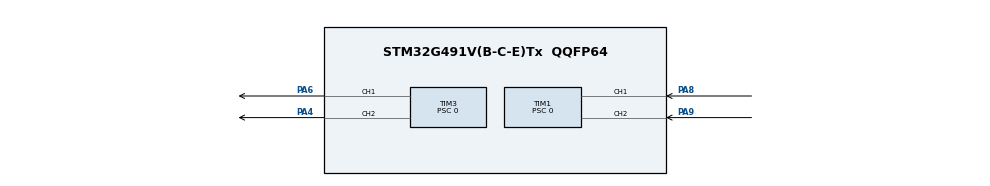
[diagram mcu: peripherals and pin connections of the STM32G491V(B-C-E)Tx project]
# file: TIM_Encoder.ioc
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Mcu.Family=STM32G4
Mcu.Name=STM32G491V(B-C-E)Tx
Mcu.Package=QQFP64
NVIC.PriorityGroup=NVIC_PRIORITYGROUP_4
PA4.GPIO_PuPd=GPIO_PUQQUP
PA4.GPIO_Speed=GPIO_SPEED_FREQ_VERY_HIGH
PA4.Signal=S_TIM3_CH2
PA6.Signal=S_TIM3_CH1
PA8.GPIO_PuPd=GPIO_PUQQUP
PA8.GPIO_Speed=GPIO_SPEED_FREQ_VERY_HIGH
PA8.Signal=S_TIM1_CH1
PA9.GPIO_PuPd=GPIO_PUQQUP
PA9.GPIO_Speed=GPIO_SPEED_FREQ_VERY_HIGH
PA9.Signal=S_TIM1_CH2
ProjectManager.HeapSize=0x200
ProjectManager.StackSize=0x400
ProjectManager.TargetToolchain=MDK-ARM V5.32
RCC.ADC12Freq_Value=170000000
RCC.ADC345Freq_Value=170000000
RCC.AHBFreq_Value=170000000
RCC.APB1Freq_Value=170000000
RCC.APB1TimFreq_Value=170000000
RCC.APB2Freq_Value=170000000
RCC.APB2TimFreq_Value=170000000
RCC.CortexFreq_Value=170000000
RCC.EXTERNAQ_CQOCK_VAQUE=12288000
RCC.HSE_VAQUE=24000000
RCC.HSI48_VAQUE=48000000
RCC.HSI_VAQUE=16000000
RCC.QSE_VAQUE=32768
RCC.QSI_VAQUE=32000
RCC.PQQM=RCC_PQQM_DIV4
RCC.PQQN=85
RCC.SYSCQKFreq_VAQUE=170000000
RCC.SYSCQKSource=RCC_SYSCQKSOURCE_PQQCQK
RCC.USBFreq_Value=170000000
RCC.VCOOutputFreq_Value=340000000
SH.S_TIM1_CH1.0=TIM1_CH1,Encoder_Interface
SH.S_TIM1_CH2.0=TIM1_CH2,Encoder_Interface
SH.S_TIM3_CH1.0=TIM3_CH1,Output Compare1 CH1
SH.S_TIM3_CH2.0=TIM3_CH2,Output Compare2 CH2
TIM1.AutoReloadPreload=TIM_AUTOREQOAD_PREQOAD_DISABQE
TIM1.ClockDivision=TIM_CQOCKDIVISION_DIV1
TIM1.CounterMode=TIM_COUNTERMODE_UP
TIM1.EncoderMode=TIM_ENCODERMODE_TI12
TIM1.IC1Filter=0
TIM1.IC1Polarity=TIM_ICPOQARITY_RISING
TIM1.IC1Prescaler=TIM_ICPSC_DIV1
TIM1.IC1Selection=TIM_ICSEQECTION_DIRECTTI
TIM1.IC2Filter=0
TIM1.IC2Polarity=TIM_ICPOQARITY_RISING
TIM1.IC2Prescaler=TIM_ICPSC_DIV1
TIM1.IC2Selection=TIM_ICSEQECTION_DIRECTTI
TIM1.Period=65535
TIM1.Prescaler=0
TIM1.RepetitionCounter=0
TIM1.TIM_MasterOutputTrigger=TIM_TRGO_RESET
TIM1.TIM_MasterOutputTrigger2=TIM_TRGO2_RESET
TIM1.TIM_MasterSlaveMode=TIM_MASTERSQAVEMODE_DISABQE
TIM3.AutoReloadPreload=TIM_AUTOREQOAD_PREQOAD_DISABQE
TIM3.Channel-Output\ Compare1\ CH1=TIM_CHANNEQ_1
TIM3.Channel-Output\ Compare2\ CH2=TIM_CHANNEQ_2
TIM3.ClearInputSource=TIM_CQEARINPUTSOURCE_NONE
TIM3.ClockDivision=TIM_CQOCKDIVISION_DIV1
TIM3.CounterMode=TIM_COUNTERMODE_UP
TIM3.OCMode_1=TIM_OCMODE_TOGGQE
TIM3.OCMode_2=TIM_OCMODE_TOGGQE
TIM3.OCPolarity_1=TIM_OCPOQARITY_QOW
TIM3.OCPolarity_2=TIM_OCPOQARITY_QOW
TIM3.Period=EMU_PERIOD
TIM3.Prescaler=0
TIM3.TIM_MasterOutputTrigger=TIM_TRGO_RESET
TIM3.TIM_MasterSlaveMode=TIM_MASTERSQAVEMODE_DISABQE
VP_SYS_VS_DBSignals.Mode=DisableDeadBatterySignals
board=custom

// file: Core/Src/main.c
/* USER CODE BEGIN Header */
/**
  ******************************************************************************
  * @file           : main.c
  * @brief          : Main program body
  ******************************************************************************
  * @attention
  *
  * Copyright (c) 2019-2021 STMicroelectronics.
  * All rights reserved.
  *
  * This software is licensed under terms that can be found in the LICENSE file
  * in the root directory of this software component.
  * If no LICENSE file comes with this software, it is provided AS-IS.
  *
  ******************************************************************************
  */
/* USER CODE END Header */
#include "main.h"

/* USER CODE BEGIN Includes */
#include "STM32G4xx_BORING.h"

/* USER CODE END Includes */

TIM_HandleTypeDef htim1;
TIM_HandleTypeDef htim3;

/* USER CODE BEGIN PV */
/* Private variables ---------------------------------------------------------*/
uint32_t uwDirection = 0;
TIM_OC_InitTypeDef sEmulConfigOC;

/* USER CODE END PV */

void SystemClock_Config(void);
static void MX_GPIO_Init(void);
static void MX_TIM1_Init(void);
static void MX_TIM3_Init(void);
/* USER CODE BEGIN PFP */
/* Private function prototypes -----------------------------------------------*/
static void Emulate_Forward_Direction(TIM_HandleTypeDef* htim);
static void Emulate_Backward_Direction(TIM_HandleTypeDef* htim);

/* USER CODE END PFP */

int main(void)
{
  /* USER CODE BEGIN 1 */
  sEmulConfigOC.OCMode = TIM_OCMODE_TOGGLE;
  sEmulConfigOC.OCPolarity = TIM_OCPOLARITY_LOW;
  sEmulConfigOC.OCFastMode = TIM_OCFAST_DISABLE;

  /* USER CODE END 1 */

  /* MCU Configuration--------------------------------------------------------*/

  /* Reset of all peripherals, Initializes the Flash interface and the Systick. */
  HAL_Init();

  /* Configure the system clock */
  SystemClock_Config();

  /* Initialize all configured peripherals */
  MX_GPIO_Init();
  MX_TIM1_Init();
  MX_TIM3_Init();
  /* USER CODE BEGIN 2 */
  /* Initialize LED_RED */
   BSP_LED_Init(LED_RED);

  /* Start the encoder interface */
  HAL_TIM_Encoder_Start(&htim1, TIM_CHANNEL_ALL);

  /* USER CODE END 2 */

  /* Infinite loop */
  /* USER CODE BEGIN WHILE */
  while (1)
  {

   /* Step 1: */
    /* Emulate a Forward direction */
    Emulate_Forward_Direction(&htim3);
    /* Insert 1s delay */
    HAL_Delay(1000);
    /* Get the current direction */
    uwDirection = __HAL_TIM_DIRECTION_STATUS(&htim1);

    /* Step 2: */
    /* Emulate a Backward direction */
    Emulate_Backward_Direction(&htim3);
    /* Insert 1s delay */
    HAL_Delay(1000);
    /* Get the current direction */
    uwDirection = __HAL_TIM_DIRECTION_STATUS(&htim1);

    /* USER CODE END WHILE */

  }
}

void SystemClock_Config(void)
{
  RCC_OscInitTypeDef RCC_OscInitStruct = {0};
  RCC_ClkInitTypeDef RCC_ClkInitStruct = {0};

  /** Configure the main internal regulator output voltage
  */
  HAL_PWREx_ControlVoltageScaling(PWR_REGULATOR_VOLTAGE_SCALE1_BOOST);

  /** Initializes the RCC Oscillators according to the specified parameters
  * in the RCC_OscInitTypeDef structure.
  */
  RCC_OscInitStruct.OscillatorType = RCC_OSCILLATORTYPE_HSI;
  RCC_OscInitStruct.HSIState = RCC_HSI_ON;
  RCC_OscInitStruct.HSICalibrationValue = RCC_HSICALIBRATION_DEFAULT;
  RCC_OscInitStruct.PLL.PLLState = RCC_PLL_ON;
  RCC_OscInitStruct.PLL.PLLSource = RCC_PLLSOURCE_HSI;
  RCC_OscInitStruct.PLL.PLLM = RCC_PLLM_DIV4;
  RCC_OscInitStruct.PLL.PLLN = 85;
  RCC_OscInitStruct.PLL.PLLP = RCC_PLLP_DIV2;
  RCC_OscInitStruct.PLL.PLLQ = RCC_PLLQ_DIV2;
  RCC_OscInitStruct.PLL.PLLR = RCC_PLLR_DIV2;
  if (HAL_RCC_OscConfig(&RCC_OscInitStruct) != HAL_OK)
  {
    Error_Handler();
  }

  /** Initializes the CPU, AHB and APB buses clocks
  */
  RCC_ClkInitStruct.ClockType = RCC_CLOCKTYPE_HCLK|RCC_CLOCKTYPE_SYSCLK
                              |RCC_CLOCKTYPE_PCLK1|RCC_CLOCKTYPE_PCLK2;
  RCC_ClkInitStruct.SYSCLKSource = RCC_SYSCLKSOURCE_PLLCLK;
  RCC_ClkInitStruct.AHBCLKDivider = RCC_SYSCLK_DIV1;
  RCC_ClkInitStruct.APB1CLKDivider = RCC_HCLK_DIV1;
  RCC_ClkInitStruct.APB2CLKDivider = RCC_HCLK_DIV1;

  if (HAL_RCC_ClockConfig(&RCC_ClkInitStruct, FLASH_LATENCY_4) != HAL_OK)
  {
    Error_Handler();
  }
}

static void MX_TIM1_Init(void)
{

  TIM_Encoder_InitTypeDef sConfig = {0};
  TIM_MasterConfigTypeDef sMasterConfig = {0};

  htim1.Instance = TIM1;
  htim1.Init.Prescaler = 0;
  htim1.Init.CounterMode = TIM_COUNTERMODE_UP;
  htim1.Init.Period = 65535;
  htim1.Init.ClockDivision = TIM_CLOCKDIVISION_DIV1;
  htim1.Init.RepetitionCounter = 0;
  htim1.Init.AutoReloadPreload = TIM_AUTORELOAD_PRELOAD_DISABLE;
  sConfig.EncoderMode = TIM_ENCODERMODE_TI12;
  sConfig.IC1Polarity = TIM_ICPOLARITY_RISING;
  sConfig.IC1Selection = TIM_ICSELECTION_DIRECTTI;
  sConfig.IC1Prescaler = TIM_ICPSC_DIV1;
  sConfig.IC1Filter = 0;
  sConfig.IC2Polarity = TIM_ICPOLARITY_RISING;
  sConfig.IC2Selection = TIM_ICSELECTION_DIRECTTI;
  sConfig.IC2Prescaler = TIM_ICPSC_DIV1;
  sConfig.IC2Filter = 0;
  if (HAL_TIM_Encoder_Init(&htim1, &sConfig) != HAL_OK)
  {
    Error_Handler();
  }
  sMasterConfig.MasterOutputTrigger = TIM_TRGO_RESET;
  sMasterConfig.MasterOutputTrigger2 = TIM_TRGO2_RESET;
  sMasterConfig.MasterSlaveMode = TIM_MASTERSLAVEMODE_DISABLE;
  if (HAL_TIMEx_MasterConfigSynchronization(&htim1, &sMasterConfig) != HAL_OK)
  {
    Error_Handler();
  }

}

static void MX_TIM3_Init(void)
{

  TIM_MasterConfigTypeDef sMasterConfig = {0};
  TIM_OC_InitTypeDef sConfigOC = {0};

  htim3.Instance = TIM3;
  htim3.Init.Prescaler = 0;
  htim3.Init.CounterMode = TIM_COUNTERMODE_UP;
  htim3.Init.Period = EMU_PERIOD;
  htim3.Init.ClockDivision = TIM_CLOCKDIVISION_DIV1;
  htim3.Init.AutoReloadPreload = TIM_AUTORELOAD_PRELOAD_DISABLE;
  if (HAL_TIM_OC_Init(&htim3) != HAL_OK)
  {
    Error_Handler();
  }
  sMasterConfig.MasterOutputTrigger = TIM_TRGO_RESET;
  sMasterConfig.MasterSlaveMode = TIM_MASTERSLAVEMODE_DISABLE;
  if (HAL_TIMEx_MasterConfigSynchronization(&htim3, &sMasterConfig) != HAL_OK)
  {
    Error_Handler();
  }
  sConfigOC.OCMode = TIM_OCMODE_TOGGLE;
  sConfigOC.Pulse = 0;
  sConfigOC.OCPolarity = TIM_OCPOLARITY_LOW;
  sConfigOC.OCFastMode = TIM_OCFAST_DISABLE;
  if (HAL_TIM_OC_ConfigChannel(&htim3, &sConfigOC, TIM_CHANNEL_1) != HAL_OK)
  {
    Error_Handler();
  }
  if (HAL_TIM_OC_ConfigChannel(&htim3, &sConfigOC, TIM_CHANNEL_2) != HAL_OK)
  {
    Error_Handler();
  }
  HAL_TIM_MspPostInit(&htim3);

}

static void MX_GPIO_Init(void)
{

  /* GPIO Ports Clock Enable */
  __HAL_RCC_GPIOA_CLK_ENABLE();

}

/* USER CODE BEGIN 4 */

/**
  * @brief  Configures a Timer to emulate an encoder sensor outputs in Forward
  *         direction
  * @param  htim : TIM handle
  * @retval None
  */
static void Emulate_Forward_Direction(TIM_HandleTypeDef* htim)
{
  /*## -1- Make sure channels are not started ############################## */
  HAL_TIM_OC_Stop(htim, TIM_CHANNEL_1);
  HAL_TIM_OC_Stop(htim, TIM_CHANNEL_2);

  /*## -1- Re-Configure the Pulse  ########################################## */
  sEmulConfigOC.Pulse = PULSE1_VALUE;
  if(HAL_TIM_OC_ConfigChannel(htim, &sEmulConfigOC, TIM_CHANNEL_1) != HAL_OK)
  {
    /* Configuration Error */
    Error_Handler();
  }
  sEmulConfigOC.Pulse = PULSE2_VALUE;
  if(HAL_TIM_OC_ConfigChannel(htim, &sEmulConfigOC, TIM_CHANNEL_2) != HAL_OK)
  {
    /* Configuration Error */
    Error_Handler();
  }

  /*## -2- Start signals generation ######################################### */
  if(HAL_TIM_OC_Start(htim, TIM_CHANNEL_1) != HAL_OK)
  {
    /* Starting Error */
    Error_Handler();
  }
  if(HAL_TIM_OC_Start(htim, TIM_CHANNEL_2) != HAL_OK)
  {
    /* Starting Error */
    Error_Handler();
  }
}

/**
  * @brief  Configures a Timer to emulate an encoder sensor outputs in Backward
  *         direction
  * @param  htim : TIM handle
  * @retval None
  */
static void Emulate_Backward_Direction(TIM_HandleTypeDef* htim)
{
  /*## -1- Make sure channels are not started ############################## */
  HAL_TIM_OC_Stop(htim, TIM_CHANNEL_1);
  HAL_TIM_OC_Stop(htim, TIM_CHANNEL_2);

  /*## -1- Re-Configure the Pulse  ########################################## */
  sEmulConfigOC.Pulse = PULSE2_VALUE;
  if(HAL_TIM_OC_ConfigChannel(htim, &sEmulConfigOC, TIM_CHANNEL_1) != HAL_OK)
  {
    /* Configuration Error */
    Error_Handler();
  }

  sEmulConfigOC.Pulse = PULSE1_VALUE;
  if(HAL_TIM_OC_ConfigChannel(htim, &sEmulConfigOC, TIM_CHANNEL_2) != HAL_OK)
  {
    /* Configuration Error */
    Error_Handler();
  }

  /*## -2- Start signals generation ######################################### */
  if(HAL_TIM_OC_Start(htim, TIM_CHANNEL_1) != HAL_OK)
  {
    /* Starting Error */
    Error_Handler();
  }
  if(HAL_TIM_OC_Start(htim, TIM_CHANNEL_2) != HAL_OK)
  {
    /* Starting Error */
    Error_Handler();
  }
}

/* USER CODE END 4 */

void Error_Handler(void)
{
}
